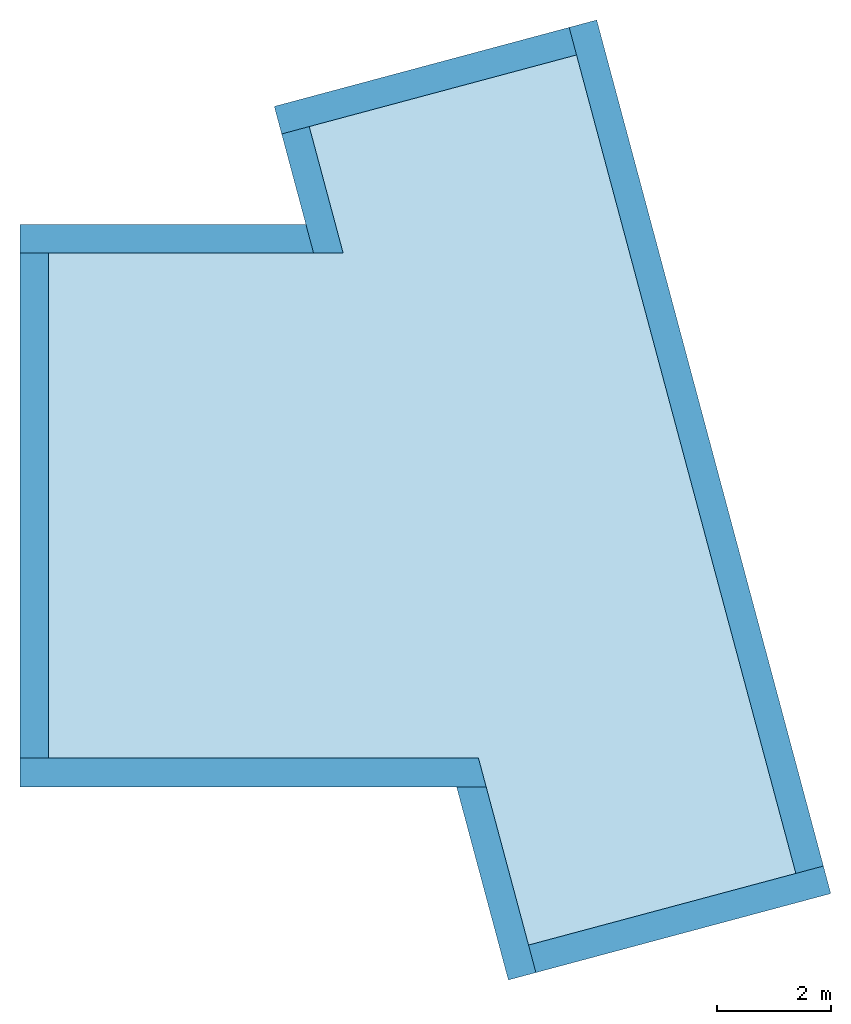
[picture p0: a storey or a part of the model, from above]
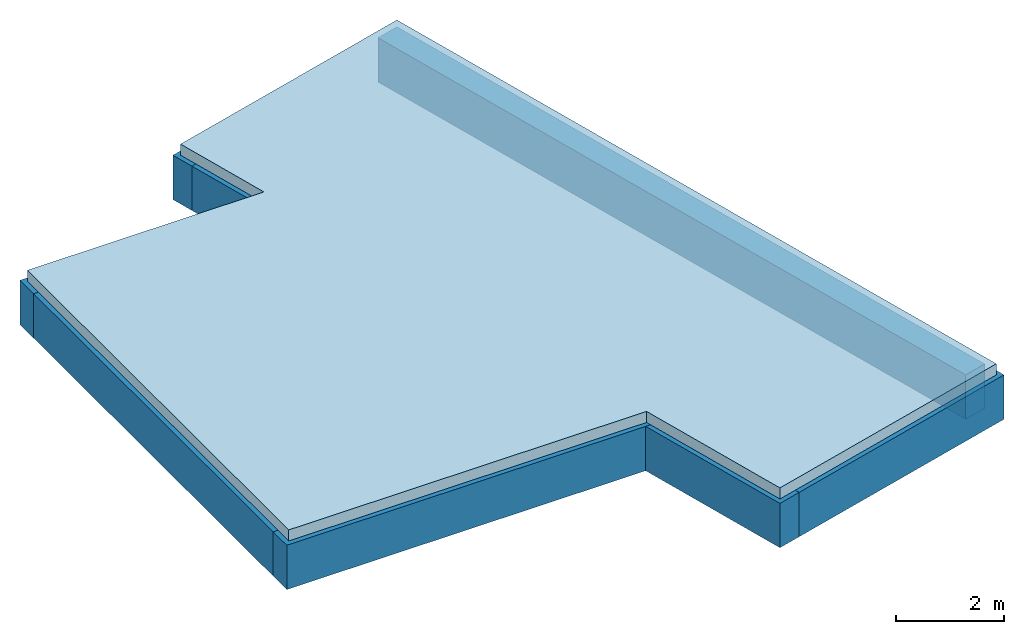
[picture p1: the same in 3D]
Properties of the parts of a building model (IFC4)

# File
Description: no view
File name: ÖBV_OEBV_Richtlinie_Baumassenkörper.ifc
Time: 2024-03-13T09:49:03
Author: Oesterreichische Bautechnik Vereinigung
Organization: OEBV
Written by: ODA SDAI 24.5
Authorization: OEBV

# IfcSite, Liegenschaft
RefLatitude: 48, 8, 10, 320000; RefLongitude: 11, 41, 19, 320000

# IfcBuildingStorey (4)
In: Gebäude
Elevation: 0 m
Name
Geschoss 01
Geschoss 02
Geschoss 03
Geschoss 04

# IfcBuildingElementProxy (3)
Name | In | Allright_Bauteil_ID
 | Geschoss 02
 | Geschoss 03 | 0120ErE0000000002
 | Geschoss 04 | 0220ErE0000000002

# IfcFooting (8)
In: Geschoss 01
Description: Streifenfundament; PredefinedType: STRIP_FOOTING; Material: C12/15
Name | Allright_Bauteil_ID
SFU_01 | 0020SFu0000000026
SFU_01 | 0020SFu0000000038
SFU_01 | 0020SFu0000000050
SFU_01 | 0020SFu0000000012
SFU_01 | 0020SFu0000000086
SFU_01 | 0020SFu0000000074
SFU_01 | 0020SFu0000000062
SFU_01 | 0020SFu0000000016

# IfcSlab, PFU_02
In: Geschoss 01
Description: Plattenfundament; PredefinedType: BASESLAB; Material: C20/25
AllplanAttributes - Allright_Bauteil_ID: 0020PFu0000000007
